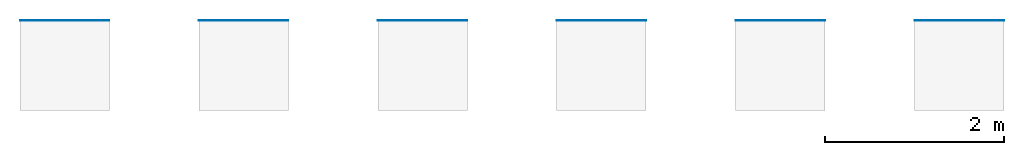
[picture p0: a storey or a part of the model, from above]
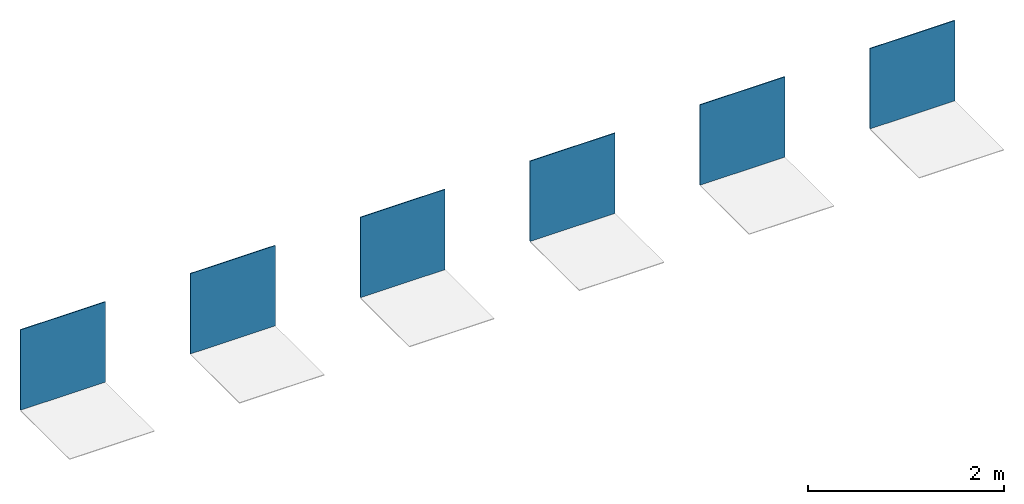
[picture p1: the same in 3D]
Properties of the parts of a building model (IFC2X3)

# File
Description: ViewDefinition [CoordinationView_V2.0]
Time: 2025-06-20T14:48:57
Written by: The EXPRESS Data Manager Version 5.02.0100.07 : 28 Aug 2013
Made in: 21.1.90.15 - Exporter 21.1.90.15 - Alternate UI 21.1.90.15
Comment: STEP Physical File produced by: The EXPRESS Data Manager Version 5.02.0100.07 : 28 Aug 2013 * Module: EDMstepFileFactory/EDMstandAlone * Creation date: Fri Jun 20 14:48:57 2025 * Host: STB002 * Database: C:\Users\LARISS~1\AppData\Local\Temp\234e31d9-e186-458c-9206-d387dea7a233\ee9d88bc-6ba1-4956-a05b-8b28d5bbadac\ifc * Database version: 5507 * Database creation date: Fri Jun 20 14:48:56 2025 * Schema: IFC2X3 * Model: DataRepository.ifc * Model creation date: Fri Jun 20 14:48:57 2025 * Header model: DataRepository.ifc_HeaderModel * Header model creation date: Fri Jun 20 14:48:57 2025 * EDMuser: sdai-user * EDMgroup: sdai-group * License ID and type: 5605 : Permanent license. Expiry date: * EDMstepFileFactory options: 020000

# IfcSite, Default
RefLatitude: 42, 24, 53, 508911; RefLongitude: -71, -15, -29, -58837; RefElevation: 0 mm
Pset_ProductRequirements - Category: Project Information

# IfcBuilding
Pset_BuildingCommon - NumberOfStoreys: 1
Pset_ProductRequirements - Category: Project Information

# IfcBuildingStorey: Level:Level 1, Level 1
LongName: Level 1; Elevation: 0 mm
Pset_AirSideSystemInformation - Name: Level 1
Pset_ProductRequirements - Name: Level 1; Category: Levels

# IfcCovering: Floor:REVIGRÉS-OMNISTONE-MOLTI-30X30-MATTRECT-BONE, Floor:REVIGRÉS-OMNISTONE-MOLTI-30X30-MATTRECT-BONE:155589
In: Level 1
Type - PredefinedType: CLADDING; Material: REVIGRÉS-OMNISTONE-MOLTI-30X30-MATTRECT-BONE 9.8 mm
Type - Pset_CoveringCommon - Reference: 312B127X61; Material: Grés porcelânico
Type - Pset_ElementShading - Roughness: 304.8 mm
Type - Pset_ManufacturerTypeInformation - Manufacturer: REVIGRÉS
Type - Pset_ProductRequirements - Category: Floors
Type - Pset_QuantityTakeOff - Reference: 312B127X61
Type - IFC.REVIGRÉS-Dados do fabricante-Floor Covering - FabricanteURL: https://www.revigres.pt/; ReferenciaModelo: Omnistone; NumeroGlobalDeItemComercial: 312B127X61; Acabamento: MATT RECT; Material: Grés porcelânico; IdentificadorDoOperadorEconomico: 501840856; UrlFabricanteArtigo: https://www.revigres.pt/colecoes/omnistone; PaisOrigem: Portugal
Type - IFC.REVIGRÉS-Dados de desempenho-Floor Covering - Rectilinearidade: ± 0.2% máx.± 0.8 mm; Ortogonalidade: ± 0.2% máx.± 1.5 mm; PlanaridadeDaSuperficie: ± 0.3% máx. ± 1.8 mm; QualidadeDaSuperficie: Cumpre; AbsorcaoDeAgua: < 0.05%; ModuloDeRuptura: > 45 N/mm²; ResistenciaAFlexao: ≥ 3500 N; ResistenciaAAbrasaoProfunda: < 120 mm³; DilatacaoTermicaLinear: ≤ 8,0x10-6 °C-1; ResistenciaAoChoqueTermico: Resiste; DurabilidadeResistenciaAoGeloDegelo: Resiste; ResistenciaAoEscorregamentoDIN51130: R10; ResistenciaAoEscorregamentoDIN51097: B; ResistenciaAoEscorregamentoENV51097: B; ResistenciaAoEscorregamentoENV12633: Class 2; ResistenciaAoEscorregamentoBS7976: >36; ResistenciaAoEscorregamentoANSIA1371: ≥0,42; ResistenciaAoDeslizamentoENV12633: Class 2; ResistenciaAoDeslizamentoBS7976: >36; ResistenciaAsManchas: Class 5; ResistenciaABaixasConcentracoesDeAcidosEAlcalis: Classe LA; ResistenciaAAltasConcentracoesDeAcidosEAlcalis: Classe HA; LibertacaoDeCadmio: 0; LibertacaoDeChumbo: 0
Type - IFC.REVIGRÉS-Dados de especificação-Floor Covering - VariacaoTonalidade: 3; NivelDeTrafego: 5; EPavimento: Sim; ERevestimento: Sim; EExterno: Sim
Type - IFC.REVIGRÉS-Dados geométricos-Floor Covering - AlturaNominal: 9.8 mm; ComprimentoNominal: 29.5 mm; LarguraNominal: 29.5 mm
Type - IFC.REVIGRÉS-Dados de sustentabilidade-Floor Covering - ItemEParcialmenteReciclado: 0; EnergiaTermicaExportada: 0; ItemENovo: Sim; ItemEReciclado: Não; VidaÚtilEsperada: 50; SubstanciasPerigosas: Não; PotencialDeEsgotamentoAbioticoDosRecursosFosseis: 203; PotencialDeEsgotamentoAbioticoDosRecursosNaoFosseisMineraisEMetais: 0.000701; PotencialDeAquecimentoGlobalBiogenico: -0.48; CombustiveisFosseisComPotencialDeAquecimentoGlobal: 13.9; PotencialDeAquecimentoGlobalUsoDoSoloEMudancaDeUsoDoSolo: 0.0246; PotencialDeEutrofizacaoFraccaoDeNutrientesQueAtingemOCompartimentoFinalDeAguaDoce: 0.000189; PotencialDeEutrofizacaoFraccaoDeNutrientesQueAtingemOCompartimentoFinalMarinho: 0.0122; EnergiaRecuperada: 0.00739; ConsumoDeAguaDoce: 0.113; UtilizacaoLiquidaDeAguaDoce: 0.113; ResiduosPerigososEliminados: 0.00221; ResiduosNaoPerigososEliminados: 1.83; MassaTotalDeResiduosRadioactivosEliminados: 0.000394; EnergiaElectricaExportada: 1.55; MateriaisParaRecuperacaoDeEnergia: 0.00739; MateriaisParaReciclagem: 0.0253; UnidadeEPD: 1 m²
Type - IFC.REVIGRÉS-Dados gerais-Floor Covering - Nome: REVIGRÉS-OMNISTONE-MOLTI-30x30-MATT RECT-BONE; TipoProduto: Prensado a seco: grupo BIa UGL | Grés porcelânico técnico; NumeroDeRegistoDAP: EPD-REV-20240006-CCC1-EN; ReferenciaDAP: -; UrlDOP: -
Classification: C3020 (Uniformat)
Pset_CoveringCommon - TotalThickness: 9.8 mm
IFC.REVIGRÉS-Dados do fabricante-Floor Covering - Type: Floor: REVIGRÉS-OMNISTONE-MOLTI-30X30-MATTRECT-BONE
IFC.REVIGRÉS-Dados de desempenho-Floor Covering - Type: Floor: REVIGRÉS-OMNISTONE-MOLTI-30X30-MATTRECT-BONE
IFC.REVIGRÉS-Dados de especificação-Floor Covering - Type: Floor: REVIGRÉS-OMNISTONE-MOLTI-30X30-MATTRECT-BONE
IFC.REVIGRÉS-Dados geométricos-Floor Covering - Type: Floor: REVIGRÉS-OMNISTONE-MOLTI-30X30-MATTRECT-BONE
IFC.REVIGRÉS-Dados de sustentabilidade-Floor Covering - Type: Floor: REVIGRÉS-OMNISTONE-MOLTI-30X30-MATTRECT-BONE

# IfcCovering: Floor:REVIGRÉS-OMNISTONE-MOLTI-30X30-MATTRECT-ICE, Floor:REVIGRÉS-OMNISTONE-MOLTI-30X30-MATTRECT-ICE:156220
In: Level 1
Type - PredefinedType: CLADDING; Material: REVIGRÉS-OMNISTONE-MOLTI-30X30-MATTRECT-ICE 9.8 mm
Type - Pset_CoveringCommon - Reference: 312B127X71; Material: Grés porcelânico
Type - Pset_ElementShading - Roughness: 304.8 mm
Type - Pset_ManufacturerTypeInformation - Manufacturer: REVIGRÉS
Type - Pset_ProductRequirements - Category: Floors
Type - Pset_QuantityTakeOff - Reference: 312B127X71
Type - IFC.REVIGRÉS-Dados do fabricante-Floor Covering - FabricanteURL: https://www.revigres.pt/; ReferenciaModelo: Omnistone; NumeroGlobalDeItemComercial: 312B127X71; Acabamento: MATT RECT; Material: Grés porcelânico; IdentificadorDoOperadorEconomico: 501840856; UrlFabricanteArtigo: https://www.revigres.pt/colecoes/omnistone; PaisOrigem: Portugal
Type - IFC.REVIGRÉS-Dados de desempenho-Floor Covering - Rectilinearidade: ± 0.2% máx.± 0.8 mm; Ortogonalidade: ± 0.2% máx.± 1.5 mm; PlanaridadeDaSuperficie: ± 0.3% máx. ± 1.8 mm; QualidadeDaSuperficie: Cumpre; AbsorcaoDeAgua: < 0.05%; ModuloDeRuptura: > 45 N/mm²; ResistenciaAFlexao: ≥ 3500 N; ResistenciaAAbrasaoProfunda: < 120 mm³; DilatacaoTermicaLinear: ≤ 8,0x10-6 °C-1; ResistenciaAoChoqueTermico: Resiste; DurabilidadeResistenciaAoGeloDegelo: Resiste; ResistenciaAoEscorregamentoDIN51130: R10; ResistenciaAoEscorregamentoDIN51097: B; ResistenciaAoEscorregamentoENV51097: B; ResistenciaAoEscorregamentoENV12633: Class 2; ResistenciaAoEscorregamentoBS7976: >36; ResistenciaAoEscorregamentoANSIA1371: ≥0,42; ResistenciaAoDeslizamentoENV12633: Class 2; ResistenciaAoDeslizamentoBS7976: >36; ResistenciaAsManchas: Class 5; ResistenciaABaixasConcentracoesDeAcidosEAlcalis: Classe LA; ResistenciaAAltasConcentracoesDeAcidosEAlcalis: Classe HA; LibertacaoDeCadmio: 0; LibertacaoDeChumbo: 0
Type - IFC.REVIGRÉS-Dados de especificação-Floor Covering - VariacaoTonalidade: 3; NivelDeTrafego: 5; EPavimento: Sim; ERevestimento: Sim; EExterno: Sim
Type - IFC.REVIGRÉS-Dados geométricos-Floor Covering - AlturaNominal: 9.8 mm; ComprimentoNominal: 29.5 mm; LarguraNominal: 29.5 mm
Type - IFC.REVIGRÉS-Dados de sustentabilidade-Floor Covering - ItemEParcialmenteReciclado: 0; EnergiaTermicaExportada: 0; ItemENovo: Sim; ItemEReciclado: Não; VidaÚtilEsperada: 50; SubstanciasPerigosas: Não; PotencialDeEsgotamentoAbioticoDosRecursosFosseis: 203; PotencialDeEsgotamentoAbioticoDosRecursosNaoFosseisMineraisEMetais: 0.000701; PotencialDeAquecimentoGlobalBiogenico: -0.48; CombustiveisFosseisComPotencialDeAquecimentoGlobal: 13.9; PotencialDeAquecimentoGlobalUsoDoSoloEMudancaDeUsoDoSolo: 0.0246; PotencialDeEutrofizacaoFraccaoDeNutrientesQueAtingemOCompartimentoFinalDeAguaDoce: 0.000189; PotencialDeEutrofizacaoFraccaoDeNutrientesQueAtingemOCompartimentoFinalMarinho: 0.0122; EnergiaRecuperada: 0.00739; ConsumoDeAguaDoce: 0.113; UtilizacaoLiquidaDeAguaDoce: 0.113; ResiduosPerigososEliminados: 0.00221; ResiduosNaoPerigososEliminados: 1.83; MassaTotalDeResiduosRadioactivosEliminados: 0.000394; EnergiaElectricaExportada: 1.55; MateriaisParaRecuperacaoDeEnergia: 0.00739; MateriaisParaReciclagem: 0.0253; UnidadeEPD: 1 m²
Type - IFC.REVIGRÉS-Dados gerais-Floor Covering - Nome: REVIGRÉS-OMNISTONE-MOLTI-30x30-MATT RECT-ICE; TipoProduto: Prensado a seco: grupo BIa UGL | Grés porcelânico técnico; NumeroDeRegistoDAP: EPD-REV-20240006-CCC1-EN; ReferenciaDAP: -; UrlDOP: -
Classification: C3020 (Uniformat)
Pset_CoveringCommon - TotalThickness: 9.8 mm
IFC.REVIGRÉS-Dados do fabricante-Floor Covering - Type: Floor: REVIGRÉS-OMNISTONE-MOLTI-30X30-MATTRECT-ICE
IFC.REVIGRÉS-Dados de desempenho-Floor Covering - Type: Floor: REVIGRÉS-OMNISTONE-MOLTI-30X30-MATTRECT-ICE
IFC.REVIGRÉS-Dados de especificação-Floor Covering - Type: Floor: REVIGRÉS-OMNISTONE-MOLTI-30X30-MATTRECT-ICE
IFC.REVIGRÉS-Dados geométricos-Floor Covering - Type: Floor: REVIGRÉS-OMNISTONE-MOLTI-30X30-MATTRECT-ICE
IFC.REVIGRÉS-Dados de sustentabilidade-Floor Covering - Type: Floor: REVIGRÉS-OMNISTONE-MOLTI-30X30-MATTRECT-ICE

# IfcCovering: Floor:REVIGRÉS-OMNISTONE-MOLTI-30X30-MATTRECT-IRON, Floor:REVIGRÉS-OMNISTONE-MOLTI-30X30-MATTRECT-IRON:156297
In: Level 1
Type - PredefinedType: CLADDING; Material: REVIGRÉS-OMNISTONE-MOLTI-30X30-MATTRECT-IRON 9.8 mm
Type - Pset_CoveringCommon - Reference: 312B127X81; Material: Grés porcelânico
Type - Pset_ElementShading - Roughness: 304.8 mm
Type - Pset_ManufacturerTypeInformation - Manufacturer: REVIGRÉS
Type - Pset_ProductRequirements - Category: Floors
Type - Pset_QuantityTakeOff - Reference: 312B127X81
Type - IFC.REVIGRÉS-Dados do fabricante-Floor Covering - FabricanteURL: https://www.revigres.pt/; ReferenciaModelo: Omnistone; NumeroGlobalDeItemComercial: 312B127X81; Acabamento: MATT RECT; Material: Grés porcelânico; IdentificadorDoOperadorEconomico: 501840856; UrlFabricanteArtigo: https://www.revigres.pt/colecoes/omnistone; PaisOrigem: Portugal
Type - IFC.REVIGRÉS-Dados de desempenho-Floor Covering - Rectilinearidade: ± 0.2% máx.± 0.8 mm; Ortogonalidade: ± 0.2% máx.± 1.5 mm; PlanaridadeDaSuperficie: ± 0.3% máx. ± 1.8 mm; QualidadeDaSuperficie: Cumpre; AbsorcaoDeAgua: < 0.05%; ModuloDeRuptura: > 45 N/mm²; ResistenciaAFlexao: ≥ 3500 N; ResistenciaAAbrasaoProfunda: < 120 mm³; DilatacaoTermicaLinear: ≤ 8,0x10-6 °C-1; ResistenciaAoChoqueTermico: Resiste; DurabilidadeResistenciaAoGeloDegelo: Resiste; ResistenciaAoEscorregamentoDIN51130: R10; ResistenciaAoEscorregamentoDIN51097: B; ResistenciaAoEscorregamentoENV51097: B; ResistenciaAoEscorregamentoENV12633: Class 2; ResistenciaAoEscorregamentoBS7976: >36; ResistenciaAoEscorregamentoANSIA1371: ≥0,42; ResistenciaAoDeslizamentoENV12633: Class 2; ResistenciaAoDeslizamentoBS7976: >36; ResistenciaAsManchas: Class 5; ResistenciaABaixasConcentracoesDeAcidosEAlcalis: Classe LA; ResistenciaAAltasConcentracoesDeAcidosEAlcalis: Classe HA; LibertacaoDeCadmio: 0; LibertacaoDeChumbo: 0
Type - IFC.REVIGRÉS-Dados de especificação-Floor Covering - VariacaoTonalidade: 3; NivelDeTrafego: 5; EPavimento: Sim; ERevestimento: Sim; EExterno: Sim
Type - IFC.REVIGRÉS-Dados geométricos-Floor Covering - AlturaNominal: 9.8 mm; ComprimentoNominal: 29.5 mm; LarguraNominal: 29.5 mm
Type - IFC.REVIGRÉS-Dados de sustentabilidade-Floor Covering - EnergiaTermicaExportada: 0; ItemENovo: Sim; ItemEParcialmenteReciclado: 0.14; ItemEReciclado: Sim; VidaÚtilEsperada: 50; SubstanciasPerigosas: Não; PotencialDeEsgotamentoAbioticoDosRecursosFosseis: 203; PotencialDeEsgotamentoAbioticoDosRecursosNaoFosseisMineraisEMetais: 0.000701; PotencialDeAquecimentoGlobalBiogenico: -0.48; CombustiveisFosseisComPotencialDeAquecimentoGlobal: 13.9; PotencialDeAquecimentoGlobalUsoDoSoloEMudancaDeUsoDoSolo: 0.0246; PotencialDeEutrofizacaoFraccaoDeNutrientesQueAtingemOCompartimentoFinalDeAguaDoce: 0.000189; PotencialDeEutrofizacaoFraccaoDeNutrientesQueAtingemOCompartimentoFinalMarinho: 0.0122; EnergiaRecuperada: 0.00739; ConsumoDeAguaDoce: 0.113; UtilizacaoLiquidaDeAguaDoce: 0.113; ResiduosPerigososEliminados: 0.00221; ResiduosNaoPerigososEliminados: 1.83; MassaTotalDeResiduosRadioactivosEliminados: 0.000394; EnergiaElectricaExportada: 1.55; MateriaisParaRecuperacaoDeEnergia: 0.00739; MateriaisParaReciclagem: 0.0253; UnidadeEPD: 1 m²
Type - IFC.REVIGRÉS-Dados gerais-Floor Covering - Nome: REVIGRÉS-OMNISTONE-MOLTI-30x30-MATT RECT-IRON; TipoProduto: Prensado a seco: grupo BIa UGL | Grés porcelânico técnico; NumeroDeRegistoDAP: EPD-REV-20240006-CCC1-EN; ReferenciaDAP: -; UrlDOP: -
Classification: C3020 (Uniformat)
Pset_CoveringCommon - TotalThickness: 9.8 mm
IFC.REVIGRÉS-Dados do fabricante-Floor Covering - Type: Floor: REVIGRÉS-OMNISTONE-MOLTI-30X30-MATTRECT-IRON
IFC.REVIGRÉS-Dados de desempenho-Floor Covering - Type: Floor: REVIGRÉS-OMNISTONE-MOLTI-30X30-MATTRECT-IRON
IFC.REVIGRÉS-Dados de especificação-Floor Covering - Type: Floor: REVIGRÉS-OMNISTONE-MOLTI-30X30-MATTRECT-IRON
IFC.REVIGRÉS-Dados geométricos-Floor Covering - Type: Floor: REVIGRÉS-OMNISTONE-MOLTI-30X30-MATTRECT-IRON
IFC.REVIGRÉS-Dados de sustentabilidade-Floor Covering - Type: Floor: REVIGRÉS-OMNISTONE-MOLTI-30X30-MATTRECT-IRON

# IfcCovering: Floor:REVIGRÉS-OMNISTONE-MOLTI-30X30-MATTRECT-JET, Floor:REVIGRÉS-OMNISTONE-MOLTI-30X30-MATTRECT-JET:156364
In: Level 1
Type - PredefinedType: CLADDING; Material: REVIGRÉS-OMNISTONE-MOLTI-30X30-MATTRECT-JET 9.8 mm
Type - Pset_CoveringCommon - Reference: 312B127X91; Material: Grés porcelânico
Type - Pset_ElementShading - Roughness: 304.8 mm
Type - Pset_ManufacturerTypeInformation - Manufacturer: REVIGRÉS
Type - Pset_ProductRequirements - Category: Floors
Type - Pset_QuantityTakeOff - Reference: 312B127X91
Type - IFC.REVIGRÉS-Dados do fabricante-Floor Covering - FabricanteURL: https://www.revigres.pt/; ReferenciaModelo: Omnistone; NumeroGlobalDeItemComercial: 312B127X91; Acabamento: MATT RECT; Material: Grés porcelânico; IdentificadorDoOperadorEconomico: 501840856; UrlFabricanteArtigo: https://www.revigres.pt/colecoes/omnistone; PaisOrigem: Portugal
Type - IFC.REVIGRÉS-Dados de desempenho-Floor Covering - Rectilinearidade: ± 0.2% máx.± 0.8 mm; Ortogonalidade: ± 0.2% máx.± 1.5 mm; PlanaridadeDaSuperficie: ± 0.3% máx. ± 1.8 mm; QualidadeDaSuperficie: Cumpre; AbsorcaoDeAgua: < 0.05%; ModuloDeRuptura: > 45 N/mm²; ResistenciaAFlexao: ≥ 3500 N; ResistenciaAAbrasaoProfunda: < 120 mm³; DilatacaoTermicaLinear: ≤ 8,0x10-6 °C-1; ResistenciaAoChoqueTermico: Resiste; DurabilidadeResistenciaAoGeloDegelo: Resiste; ResistenciaAoEscorregamentoDIN51130: R10; ResistenciaAoEscorregamentoDIN51097: B; ResistenciaAoEscorregamentoENV51097: B; ResistenciaAoEscorregamentoENV12633: Class 2; ResistenciaAoEscorregamentoBS7976: >36; ResistenciaAoEscorregamentoANSIA1371: ≥0,42; ResistenciaAoDeslizamentoENV12633: Class 2; ResistenciaAoDeslizamentoBS7976: >36; ResistenciaAsManchas: Class 5; ResistenciaABaixasConcentracoesDeAcidosEAlcalis: Classe LA; ResistenciaAAltasConcentracoesDeAcidosEAlcalis: Classe HA; LibertacaoDeCadmio: 0; LibertacaoDeChumbo: 0
Type - IFC.REVIGRÉS-Dados de especificação-Floor Covering - VariacaoTonalidade: 3; NivelDeTrafego: 5; EPavimento: Sim; ERevestimento: Sim; EExterno: Sim
Type - IFC.REVIGRÉS-Dados geométricos-Floor Covering - AlturaNominal: 9.8 mm; ComprimentoNominal: 29.5 mm; LarguraNominal: 29.5 mm
Type - IFC.REVIGRÉS-Dados de sustentabilidade-Floor Covering - ItemEParcialmenteReciclado: 0; EnergiaTermicaExportada: 0; ItemENovo: Sim; ItemEReciclado: Não; VidaÚtilEsperada: 50; SubstanciasPerigosas: Não; PotencialDeEsgotamentoAbioticoDosRecursosFosseis: 203; PotencialDeEsgotamentoAbioticoDosRecursosNaoFosseisMineraisEMetais: 0.000701; PotencialDeAquecimentoGlobalBiogenico: -0.48; CombustiveisFosseisComPotencialDeAquecimentoGlobal: 13.9; PotencialDeAquecimentoGlobalUsoDoSoloEMudancaDeUsoDoSolo: 0.0246; PotencialDeEutrofizacaoFraccaoDeNutrientesQueAtingemOCompartimentoFinalDeAguaDoce: 0.000189; PotencialDeEutrofizacaoFraccaoDeNutrientesQueAtingemOCompartimentoFinalMarinho: 0.0122; EnergiaRecuperada: 0.00739; ConsumoDeAguaDoce: 0.113; UtilizacaoLiquidaDeAguaDoce: 0.113; ResiduosPerigososEliminados: 0.00221; ResiduosNaoPerigososEliminados: 1.83; MassaTotalDeResiduosRadioactivosEliminados: 0.000394; EnergiaElectricaExportada: 1.55; MateriaisParaRecuperacaoDeEnergia: 0.00739; MateriaisParaReciclagem: 0.0253; UnidadeEPD: 1 m²
Type - IFC.REVIGRÉS-Dados gerais-Floor Covering - Nome: REVIGRÉS-OMNISTONE-MOLTI-30x30-MATT RECT-JET; TipoProduto: Prensado a seco: grupo BIa UGL | Grés porcelânico técnico; NumeroDeRegistoDAP: EPD-REV-20240006-CCC1-EN; ReferenciaDAP: -; UrlDOP: -
Classification: C3020 (Uniformat)
Pset_CoveringCommon - TotalThickness: 9.8 mm
IFC.REVIGRÉS-Dados do fabricante-Floor Covering - Type: Floor: REVIGRÉS-OMNISTONE-MOLTI-30X30-MATTRECT-JET
IFC.REVIGRÉS-Dados de desempenho-Floor Covering - Type: Floor: REVIGRÉS-OMNISTONE-MOLTI-30X30-MATTRECT-JET
IFC.REVIGRÉS-Dados de especificação-Floor Covering - Type: Floor: REVIGRÉS-OMNISTONE-MOLTI-30X30-MATTRECT-JET
IFC.REVIGRÉS-Dados geométricos-Floor Covering - Type: Floor: REVIGRÉS-OMNISTONE-MOLTI-30X30-MATTRECT-JET
IFC.REVIGRÉS-Dados de sustentabilidade-Floor Covering - Type: Floor: REVIGRÉS-OMNISTONE-MOLTI-30X30-MATTRECT-JET

# IfcCovering: Floor:REVIGRÉS-OMNISTONE-MOLTI-30X30-MATTRECT-PLATINA, Floor:REVIGRÉS-OMNISTONE-MOLTI-30X30-MATTRECT-PLATINA:156444
In: Level 1
Type - PredefinedType: CLADDING; Material: REVIGRÉS-OMNISTONE-MOLTI-30X30-MATTRECT-PLATINA 9.8 mm
Type - Pset_CoveringCommon - Reference: 312B128X01; Material: Grés porcelânico
Type - Pset_ElementShading - Roughness: 304.8 mm
Type - Pset_ManufacturerTypeInformation - Manufacturer: REVIGRÉS
Type - Pset_ProductRequirements - Category: Floors
Type - Pset_QuantityTakeOff - Reference: 312B128X01
Type - IFC.REVIGRÉS-Dados do fabricante-Floor Covering - FabricanteURL: https://www.revigres.pt/; ReferenciaModelo: Omnistone; NumeroGlobalDeItemComercial: 312B128X01; Acabamento: MATT RECT; Material: Grés porcelânico; IdentificadorDoOperadorEconomico: 501840856; UrlFabricanteArtigo: https://www.revigres.pt/colecoes/omnistone; PaisOrigem: Portugal
Type - IFC.REVIGRÉS-Dados de desempenho-Floor Covering - Rectilinearidade: ± 0.2% máx.± 0.8 mm; Ortogonalidade: ± 0.2% máx.± 1.5 mm; PlanaridadeDaSuperficie: ± 0.3% máx. ± 1.8 mm; QualidadeDaSuperficie: Cumpre; AbsorcaoDeAgua: < 0.05%; ModuloDeRuptura: > 45 N/mm²; ResistenciaAFlexao: ≥ 3500 N; ResistenciaAAbrasaoProfunda: < 120 mm³; DilatacaoTermicaLinear: ≤ 8,0x10-6 °C-1; ResistenciaAoChoqueTermico: Resiste; DurabilidadeResistenciaAoGeloDegelo: Resiste; ResistenciaAoEscorregamentoDIN51130: R10; ResistenciaAoEscorregamentoDIN51097: B; ResistenciaAoEscorregamentoENV51097: B; ResistenciaAoEscorregamentoENV12633: Class 2; ResistenciaAoEscorregamentoBS7976: >36; ResistenciaAoEscorregamentoANSIA1371: ≥0,42; ResistenciaAoDeslizamentoENV12633: Class 2; ResistenciaAoDeslizamentoBS7976: >36; ResistenciaAsManchas: Class 5; ResistenciaABaixasConcentracoesDeAcidosEAlcalis: Classe LA; ResistenciaAAltasConcentracoesDeAcidosEAlcalis: Classe HA; LibertacaoDeCadmio: 0; LibertacaoDeChumbo: 0
Type - IFC.REVIGRÉS-Dados de especificação-Floor Covering - VariacaoTonalidade: 3; NivelDeTrafego: 5; EPavimento: Sim; ERevestimento: Sim; EExterno: Sim
Type - IFC.REVIGRÉS-Dados geométricos-Floor Covering - AlturaNominal: 9.8 mm; ComprimentoNominal: 29.5 mm; LarguraNominal: 29.5 mm
Type - IFC.REVIGRÉS-Dados de sustentabilidade-Floor Covering - ItemEParcialmenteReciclado: 0; EnergiaTermicaExportada: 0; ItemENovo: Sim; ItemEReciclado: Não; VidaÚtilEsperada: 50; SubstanciasPerigosas: Não; PotencialDeEsgotamentoAbioticoDosRecursosFosseis: 203; PotencialDeEsgotamentoAbioticoDosRecursosNaoFosseisMineraisEMetais: 0.000701; PotencialDeAquecimentoGlobalBiogenico: -0.48; CombustiveisFosseisComPotencialDeAquecimentoGlobal: 13.9; PotencialDeAquecimentoGlobalUsoDoSoloEMudancaDeUsoDoSolo: 0.0246; PotencialDeEutrofizacaoFraccaoDeNutrientesQueAtingemOCompartimentoFinalDeAguaDoce: 0.000189; PotencialDeEutrofizacaoFraccaoDeNutrientesQueAtingemOCompartimentoFinalMarinho: 0.0122; EnergiaRecuperada: 0.00739; ConsumoDeAguaDoce: 0.113; UtilizacaoLiquidaDeAguaDoce: 0.113; ResiduosPerigososEliminados: 0.00221; ResiduosNaoPerigososEliminados: 1.83; MassaTotalDeResiduosRadioactivosEliminados: 0.000394; EnergiaElectricaExportada: 1.55; MateriaisParaRecuperacaoDeEnergia: 0.00739; MateriaisParaReciclagem: 0.0253; UnidadeEPD: 1 m²
Type - IFC.REVIGRÉS-Dados gerais-Floor Covering - Nome: REVIGRÉS-OMNISTONE-MOLTI-30x30-MATT RECT-PLATINA; TipoProduto: Prensado a seco: grupo BIa UGL | Grés porcelânico técnico; NumeroDeRegistoDAP: EPD-REV-20240006-CCC1-EN; ReferenciaDAP: -; UrlDOP: -
Classification: C3020 (Uniformat)
Pset_CoveringCommon - TotalThickness: 9.8 mm
IFC.REVIGRÉS-Dados do fabricante-Floor Covering - Type: Floor: REVIGRÉS-OMNISTONE-MOLTI-30X30-MATTRECT-PLATINA
IFC.REVIGRÉS-Dados de desempenho-Floor Covering - Type: Floor: REVIGRÉS-OMNISTONE-MOLTI-30X30-MATTRECT-PLATINA
IFC.REVIGRÉS-Dados de especificação-Floor Covering - Type: Floor: REVIGRÉS-OMNISTONE-MOLTI-30X30-MATTRECT-PLATINA
IFC.REVIGRÉS-Dados geométricos-Floor Covering - Type: Floor: REVIGRÉS-OMNISTONE-MOLTI-30X30-MATTRECT-PLATINA
IFC.REVIGRÉS-Dados de sustentabilidade-Floor Covering - Type: Floor: REVIGRÉS-OMNISTONE-MOLTI-30X30-MATTRECT-PLATINA

# IfcCovering: Floor:REVIGRÉS-OMNISTONE-MOLTI-30X30-MATTRECT-ROPE, Floor:REVIGRÉS-OMNISTONE-MOLTI-30X30-MATTRECT-ROPE:156527
In: Level 1
Type - PredefinedType: CLADDING; Material: REVIGRÉS-OMNISTONE-MOLTI-30X30-MATTRECT-ROPE 9.8 mm
Type - Pset_CoveringCommon - Reference: 312B128X11; Material: Grés porcelânico
Type - Pset_ElementShading - Roughness: 304.8 mm
Type - Pset_ManufacturerTypeInformation - Manufacturer: REVIGRÉS
Type - Pset_ProductRequirements - Category: Floors
Type - Pset_QuantityTakeOff - Reference: 312B128X11
Type - IFC.REVIGRÉS-Dados do fabricante-Floor Covering - FabricanteURL: https://www.revigres.pt/; ReferenciaModelo: Omnistone; NumeroGlobalDeItemComercial: 312B128X11; Acabamento: MATT RECT; Material: Grés porcelânico; IdentificadorDoOperadorEconomico: 501840856; UrlFabricanteArtigo: https://www.revigres.pt/colecoes/omnistone; PaisOrigem: Portugal
Type - IFC.REVIGRÉS-Dados de desempenho-Floor Covering - Rectilinearidade: ± 0.2% máx.± 0.8 mm; Ortogonalidade: ± 0.2% máx.± 1.5 mm; PlanaridadeDaSuperficie: ± 0.3% máx. ± 1.8 mm; QualidadeDaSuperficie: Cumpre; AbsorcaoDeAgua: < 0.05%; ModuloDeRuptura: > 45 N/mm²; ResistenciaAFlexao: ≥ 3500 N; ResistenciaAAbrasaoProfunda: < 120 mm³; DilatacaoTermicaLinear: ≤ 8,0x10-6 °C-1; ResistenciaAoChoqueTermico: Resiste; DurabilidadeResistenciaAoGeloDegelo: Resiste; ResistenciaAoEscorregamentoDIN51130: R10; ResistenciaAoEscorregamentoDIN51097: B; ResistenciaAoEscorregamentoENV51097: B; ResistenciaAoEscorregamentoENV12633: Class 2; ResistenciaAoEscorregamentoBS7976: >36; ResistenciaAoEscorregamentoANSIA1371: ≥0,42; ResistenciaAoDeslizamentoENV12633: Class 2; ResistenciaAoDeslizamentoBS7976: >36; ResistenciaAsManchas: Class 5; ResistenciaABaixasConcentracoesDeAcidosEAlcalis: Classe LA; ResistenciaAAltasConcentracoesDeAcidosEAlcalis: Classe HA; LibertacaoDeCadmio: 0; LibertacaoDeChumbo: 0
Type - IFC.REVIGRÉS-Dados de especificação-Floor Covering - VariacaoTonalidade: 3; NivelDeTrafego: 5; EPavimento: Sim; ERevestimento: Sim; EExterno: Sim
Type - IFC.REVIGRÉS-Dados geométricos-Floor Covering - AlturaNominal: 9.8 mm; ComprimentoNominal: 29.5 mm; LarguraNominal: 29.5 mm
Type - IFC.REVIGRÉS-Dados de sustentabilidade-Floor Covering - ItemEParcialmenteReciclado: 0; EnergiaTermicaExportada: 0; ItemENovo: Sim; ItemEReciclado: Não; VidaÚtilEsperada: 50; SubstanciasPerigosas: Não; PotencialDeEsgotamentoAbioticoDosRecursosFosseis: 203; PotencialDeEsgotamentoAbioticoDosRecursosNaoFosseisMineraisEMetais: 0.000701; PotencialDeAquecimentoGlobalBiogenico: -0.48; CombustiveisFosseisComPotencialDeAquecimentoGlobal: 13.9; PotencialDeAquecimentoGlobalUsoDoSoloEMudancaDeUsoDoSolo: 0.0246; PotencialDeEutrofizacaoFraccaoDeNutrientesQueAtingemOCompartimentoFinalDeAguaDoce: 0.000189; PotencialDeEutrofizacaoFraccaoDeNutrientesQueAtingemOCompartimentoFinalMarinho: 0.0122; EnergiaRecuperada: 0.00739; ConsumoDeAguaDoce: 0.113; UtilizacaoLiquidaDeAguaDoce: 0.113; ResiduosPerigososEliminados: 0.00221; ResiduosNaoPerigososEliminados: 1.83; MassaTotalDeResiduosRadioactivosEliminados: 0.000394; EnergiaElectricaExportada: 1.55; MateriaisParaRecuperacaoDeEnergia: 0.00739; MateriaisParaReciclagem: 0.0253; UnidadeEPD: 1 m²
Type - IFC.REVIGRÉS-Dados gerais-Floor Covering - Nome: REVIGRÉS-OMNISTONE-MOLTI-30x30-MATT RECT-ROPE; TipoProduto: Prensado a seco: grupo BIa UGL | Grés porcelânico técnico; NumeroDeRegistoDAP: EPD-REV-20240006-CCC1-EN; ReferenciaDAP: -; UrlDOP: -
Classification: C3020 (Uniformat)
Pset_CoveringCommon - TotalThickness: 9.8 mm
IFC.REVIGRÉS-Dados do fabricante-Floor Covering - Type: Floor: REVIGRÉS-OMNISTONE-MOLTI-30X30-MATTRECT-ROPE
IFC.REVIGRÉS-Dados de desempenho-Floor Covering - Type: Floor: REVIGRÉS-OMNISTONE-MOLTI-30X30-MATTRECT-ROPE
IFC.REVIGRÉS-Dados de especificação-Floor Covering - Type: Floor: REVIGRÉS-OMNISTONE-MOLTI-30X30-MATTRECT-ROPE
IFC.REVIGRÉS-Dados geométricos-Floor Covering - Type: Floor: REVIGRÉS-OMNISTONE-MOLTI-30X30-MATTRECT-ROPE
IFC.REVIGRÉS-Dados de sustentabilidade-Floor Covering - Type: Floor: REVIGRÉS-OMNISTONE-MOLTI-30X30-MATTRECT-ROPE

# IfcWallStandardCase: Basic Wall:REVIGRÉS-OMNISTONE-MOLTI-30X30-MATTRECT-BONE, Basic Wall:REVIGRÉS-OMNISTONE-MOLTI-30X30-MATTRECT-BONE:155597
In: Level 1
Type - PredefinedType: STANDARD; Material: REVIGRÉS-OMNISTONE-MOLTI-30X30-MATTRECT-BONE 9.8 mm
Type - Pset_ElementShading - Roughness: 304.8 mm
Type - Pset_ManufacturerTypeInformation - Manufacturer: REVIGRÉS
Type - Pset_ProductRequirements - Category: Walls
Type - Pset_QuantityTakeOff - Reference: 312B127X61
Type - Pset_ReinforcementBarPitchOfWall - Description: Stone effect in wall and floor porcelain tile.; Reference: 312B127X61
Type - Pset_WallCommon - Reference: 312B127X61; IsExternal: no
Type - IFC.REVIGRÉS-Dados do fabricante-Wall Covering - FabricanteURL: https://www.revigres.pt/; ReferenciaModelo: Omnistone; NumeroGlobalDeItemComercial: 312B127X61; Acabamento: MATT RECT; Material: Grés porcelânico; IdentificadorDoOperadorEconomico: 501840856; UrlFabricanteArtigo: https://www.revigres.pt/colecoes/omnistone; PaisOrigem: Portugal
Type - IFC.REVIGRÉS-Dados de desempenho-Wall Covering - Rectilinearidade: ± 0.2% máx.± 0.8 mm; Ortogonalidade: ± 0.2% máx.± 1.5 mm; PlanaridadeDaSuperficie: ± 0.3% máx. ± 1.8 mm; QualidadeDaSuperficie: Cumpre; AbsorcaoDeAgua: < 0.05%; ModuloDeRuptura: > 45 N/mm²; ResistenciaAFlexao: ≥ 3500 N; ResistenciaAAbrasaoProfunda: < 120 mm³; DilatacaoTermicaLinear: ≤ 8,0x10-6 °C-1; ResistenciaAoChoqueTermico: Resiste; DurabilidadeResistenciaAoGeloDegelo: Resiste; ResistenciaAoEscorregamentoDIN51130: R10; ResistenciaAoEscorregamentoDIN51097: B; ResistenciaAoEscorregamentoENV51097: B; ResistenciaAoEscorregamentoENV12633: Class 2; ResistenciaAoEscorregamentoBS7976: >36; ResistenciaAoEscorregamentoANSIA1371: ≥0,42; ResistenciaAoDeslizamentoENV12633: Class 2; ResistenciaAoDeslizamentoBS7976: >36; ResistenciaAsManchas: Class 5; ResistenciaABaixasConcentracoesDeAcidosEAlcalis: Classe LA; ResistenciaAAltasConcentracoesDeAcidosEAlcalis: Classe HA; LibertacaoDeCadmio: 0; LibertacaoDeChumbo: 0
Type - IFC.REVIGRÉS-Dados de especificação-Wall Covering - VariacaoTonalidade: 3; NivelDeTrafego: 5; EPavimento: Sim; ERevestimento: Sim; EExterno: Sim
Type - IFC.REVIGRÉS-Dados geométricos-Wall Covering - AlturaNominal: 9.8 mm; ComprimentoNominal: 29.5 mm; LarguraNominal: 29.5 mm
Type - IFC.REVIGRÉS-Dados de sustentabilidade-Wall Covering - ItemEParcialmenteReciclado: 0; EnergiaTermicaExportada: 0; ItemENovo: Sim; ItemEReciclado: Não; VidaÚtilEsperada: 50; SubstanciasPerigosas: Não; PotencialDeEsgotamentoAbioticoDosRecursosFosseis: 203; PotencialDeEsgotamentoAbioticoDosRecursosNaoFosseisMineraisEMetais: 0.000701; PotencialDeAquecimentoGlobalBiogenico: -0.48; CombustiveisFosseisComPotencialDeAquecimentoGlobal: 13.9; PotencialDeAquecimentoGlobalUsoDoSoloEMudancaDeUsoDoSolo: 0.0246; PotencialDeEutrofizacaoFraccaoDeNutrientesQueAtingemOCompartimentoFinalDeAguaDoce: 0.000189; PotencialDeEutrofizacaoFraccaoDeNutrientesQueAtingemOCompartimentoFinalMarinho: 0.0122; PotencialPrivacaoDeAguaConsumoDeAguaPonderado: 4.5; EnergiaRecuperada: 0.00739; ConsumoDeAguaDoce: 0.113; UtilizacaoLiquidaDeAguaDoce: 0.113; ResiduosPerigososEliminados: 0.00221; ResiduosNaoPerigososEliminados: 1.83; MassaTotalDeResiduosRadioactivosEliminados: 0.000394; EnergiaElectricaExportada: 1.55; MateriaisParaRecuperacaoDeEnergia: 0.00739; MateriaisParaReciclagem: 0.0253; UnidadeEPD: 1 m²
Type - IFC.REVIGRÉS-Dados gerais-Wall Covering - Nome: REVIGRÉS-OMNISTONE-MOLTI-30x30-MATT RECT-BONE; TipoProduto: Prensado a seco: grupo BIa UGL | Grés porcelânico técnico; NumeroDeRegistoDAP: EPD-REV-20240006-CCC1-EN; ReferenciaDAP: -; UrlDOP: -
Classification: C3010 (Uniformat)
Pset_WallCommon - ExtendToStructure: no; LoadBearing: no
IFC.REVIGRÉS-Dados do fabricante-Wall Covering - Type: Basic Wall: REVIGRÉS-OMNISTONE-MOLTI-30X30-MATTRECT-BONE
IFC.REVIGRÉS-Dados de desempenho-Wall Covering - Type: Basic Wall: REVIGRÉS-OMNISTONE-MOLTI-30X30-MATTRECT-BONE
IFC.REVIGRÉS-Dados de especificação-Wall Covering - Type: Basic Wall: REVIGRÉS-OMNISTONE-MOLTI-30X30-MATTRECT-BONE
IFC.REVIGRÉS-Dados geométricos-Wall Covering - Type: Basic Wall: REVIGRÉS-OMNISTONE-MOLTI-30X30-MATTRECT-BONE
IFC.REVIGRÉS-Dados de sustentabilidade-Wall Covering - Type: Basic Wall: REVIGRÉS-OMNISTONE-MOLTI-30X30-MATTRECT-BONE

# IfcWallStandardCase: Basic Wall:REVIGRÉS-OMNISTONE-MOLTI-30X30-MATTRECT-ICE, Basic Wall:REVIGRÉS-OMNISTONE-MOLTI-30X30-MATTRECT-ICE:156225
In: Level 1
Type - PredefinedType: STANDARD; Material: REVIGRÉS-OMNISTONE-MOLTI-30X30-MATTRECT-ICE 9.8 mm
Type - Pset_ElementShading - Roughness: 304.8 mm
Type - Pset_ManufacturerTypeInformation - Manufacturer: REVIGRÉS
Type - Pset_ProductRequirements - Category: Walls
Type - Pset_QuantityTakeOff - Reference: 312B127X71
Type - Pset_ReinforcementBarPitchOfWall - Description: Stone effect in wall and floor porcelain tile; Reference: 312B127X71
Type - Pset_WallCommon - IsExternal: no; Reference: 312B127X71
Type - IFC.REVIGRÉS-Dados do fabricante-Wall Covering - FabricanteURL: https://www.revigres.pt/; ReferenciaModelo: Omnistone; NumeroGlobalDeItemComercial: 312B127X71; Acabamento: MATT RECT; Material: Grés porcelânico; IdentificadorDoOperadorEconomico: 501840856; UrlFabricanteArtigo: https://www.revigres.pt/colecoes/omnistone; PaisOrigem: Portugal
Type - IFC.REVIGRÉS-Dados de desempenho-Wall Covering - Rectilinearidade: ± 0.2% máx.± 0.8 mm; Ortogonalidade: ± 0.2% máx.± 1.5 mm; PlanaridadeDaSuperficie: ± 0.3% máx. ± 1.8 mm; QualidadeDaSuperficie: Cumpre; AbsorcaoDeAgua: < 0.05%; ModuloDeRuptura: > 45 N/mm²; ResistenciaAFlexao: ≥ 3500 N; ResistenciaAAbrasaoProfunda: < 120 mm³; DilatacaoTermicaLinear: ≤ 8,0x10-6 °C-1; ResistenciaAoChoqueTermico: Resiste; DurabilidadeResistenciaAoGeloDegelo: Resiste; ResistenciaAoEscorregamentoDIN51130: R10; ResistenciaAoEscorregamentoDIN51097: B; ResistenciaAoEscorregamentoENV51097: B; ResistenciaAoEscorregamentoENV12633: Class 2; ResistenciaAoEscorregamentoBS7976: >36; ResistenciaAoEscorregamentoANSIA1371: ≥0,42; ResistenciaAoDeslizamentoENV12633: Class 2; ResistenciaAoDeslizamentoBS7976: >36; ResistenciaAsManchas: Class 5; ResistenciaABaixasConcentracoesDeAcidosEAlcalis: Classe LA; ResistenciaAAltasConcentracoesDeAcidosEAlcalis: Classe HA; LibertacaoDeCadmio: 0; LibertacaoDeChumbo: 0
Type - IFC.REVIGRÉS-Dados de especificação-Wall Covering - VariacaoTonalidade: 3; NivelDeTrafego: 5; EPavimento: Sim; ERevestimento: Sim; EExterno: Sim
Type - IFC.REVIGRÉS-Dados geométricos-Wall Covering - AlturaNominal: 9.8 mm; ComprimentoNominal: 29.5 mm; LarguraNominal: 29.5 mm
Type - IFC.REVIGRÉS-Dados de sustentabilidade-Wall Covering - ItemEParcialmenteReciclado: 0; EnergiaTermicaExportada: 0; PotencialPrivacaoDeAguaConsumoDeAguaPonderado: 4.5; ItemENovo: Sim; ItemEReciclado: Não; VidaÚtilEsperada: 50; SubstanciasPerigosas: Não; PotencialDeEsgotamentoAbioticoDosRecursosFosseis: 203; PotencialDeEsgotamentoAbioticoDosRecursosNaoFosseisMineraisEMetais: 0.000701; PotencialDeAquecimentoGlobalBiogenico: -0.48; CombustiveisFosseisComPotencialDeAquecimentoGlobal: 13.9; PotencialDeAquecimentoGlobalUsoDoSoloEMudancaDeUsoDoSolo: 0.0246; PotencialDeEutrofizacaoFraccaoDeNutrientesQueAtingemOCompartimentoFinalDeAguaDoce: 0.000189; PotencialDeEutrofizacaoFraccaoDeNutrientesQueAtingemOCompartimentoFinalMarinho: 0.0122; EnergiaRecuperada: 0.00739; ConsumoDeAguaDoce: 0.113; UtilizacaoLiquidaDeAguaDoce: 0.113; ResiduosPerigososEliminados: 0.00221; ResiduosNaoPerigososEliminados: 1.83; MassaTotalDeResiduosRadioactivosEliminados: 0.000394; EnergiaElectricaExportada: 1.55; MateriaisParaRecuperacaoDeEnergia: 0.00739; MateriaisParaReciclagem: 0.0253; UnidadeEPD: 1 m²
Type - IFC.REVIGRÉS-Dados gerais-Wall Covering - Nome: REVIGRÉS-OMNISTONE-MOLTI-30x30-MATT RECT-ICE; TipoProduto: Prensado a seco: grupo BIa UGL | Grés porcelânico técnico; NumeroDeRegistoDAP: EPD-REV-20240006-CCC1-EN; ReferenciaDAP: -; UrlDOP: -
Classification: C3010 (Uniformat)
Pset_WallCommon - ExtendToStructure: no; LoadBearing: no
IFC.REVIGRÉS-Dados do fabricante-Wall Covering - Type: Basic Wall: REVIGRÉS-OMNISTONE-MOLTI-30X30-MATTRECT-ICE
IFC.REVIGRÉS-Dados de desempenho-Wall Covering - Type: Basic Wall: REVIGRÉS-OMNISTONE-MOLTI-30X30-MATTRECT-ICE
IFC.REVIGRÉS-Dados de especificação-Wall Covering - Type: Basic Wall: REVIGRÉS-OMNISTONE-MOLTI-30X30-MATTRECT-ICE
IFC.REVIGRÉS-Dados geométricos-Wall Covering - Type: Basic Wall: REVIGRÉS-OMNISTONE-MOLTI-30X30-MATTRECT-ICE
IFC.REVIGRÉS-Dados de sustentabilidade-Wall Covering - Type: Basic Wall: REVIGRÉS-OMNISTONE-MOLTI-30X30-MATTRECT-ICE

# IfcWallStandardCase: Basic Wall:REVIGRÉS-OMNISTONE-MOLTI-30X30-MATTRECT-IRON, Basic Wall:REVIGRÉS-OMNISTONE-MOLTI-30X30-MATTRECT-IRON:156302
In: Level 1
Type - PredefinedType: STANDARD; Material: REVIGRÉS-OMNISTONE-MOLTI-30X30-MATTRECT-IRON 9.8 mm
Type - Pset_ElementShading - Roughness: 304.8 mm
Type - Pset_ManufacturerTypeInformation - Manufacturer: REVIGRÉS
Type - Pset_ProductRequirements - Category: Walls
Type - Pset_QuantityTakeOff - Reference: 312B127X81
Type - Pset_ReinforcementBarPitchOfWall - Description: Stone effect in wall and floor porcelain tile; Reference: 312B127X81
Type - Pset_WallCommon - IsExternal: no; Reference: 312B127X81
Type - IFC.REVIGRÉS-Dados do fabricante-Wall Covering - FabricanteURL: https://www.revigres.pt/; ReferenciaModelo: Omnistone; NumeroGlobalDeItemComercial: 312B127X81; Acabamento: MATT RECT; Material: Grés porcelânico; IdentificadorDoOperadorEconomico: 501840856; UrlFabricanteArtigo: https://www.revigres.pt/colecoes/omnistone; PaisOrigem: Portugal
Type - IFC.REVIGRÉS-Dados de desempenho-Wall Covering - Rectilinearidade: ± 0.2% máx.± 0.8 mm; Ortogonalidade: ± 0.2% máx.± 1.5 mm; PlanaridadeDaSuperficie: ± 0.3% máx. ± 1.8 mm; QualidadeDaSuperficie: Cumpre; AbsorcaoDeAgua: < 0.05%; ModuloDeRuptura: > 45 N/mm²; ResistenciaAFlexao: ≥ 3500 N; ResistenciaAAbrasaoProfunda: < 120 mm³; DilatacaoTermicaLinear: ≤ 8,0x10-6 °C-1; ResistenciaAoChoqueTermico: Resiste; DurabilidadeResistenciaAoGeloDegelo: Resiste; ResistenciaAoEscorregamentoDIN51130: R10; ResistenciaAoEscorregamentoDIN51097: B; ResistenciaAoEscorregamentoENV51097: B; ResistenciaAoEscorregamentoENV12633: Class 2; ResistenciaAoEscorregamentoBS7976: >36; ResistenciaAoEscorregamentoANSIA1371: ≥0,42; ResistenciaAoDeslizamentoENV12633: Class 2; ResistenciaAoDeslizamentoBS7976: >36; ResistenciaAsManchas: Class 5; ResistenciaABaixasConcentracoesDeAcidosEAlcalis: Classe LA; ResistenciaAAltasConcentracoesDeAcidosEAlcalis: Classe HA; LibertacaoDeCadmio: 0; LibertacaoDeChumbo: 0
Type - IFC.REVIGRÉS-Dados de especificação-Wall Covering - VariacaoTonalidade: 3; NivelDeTrafego: 5; EPavimento: Sim; ERevestimento: Sim; EExterno: Sim
Type - IFC.REVIGRÉS-Dados geométricos-Wall Covering - AlturaNominal: 9.8 mm; ComprimentoNominal: 29.5 mm; LarguraNominal: 29.5 mm
Type - IFC.REVIGRÉS-Dados de sustentabilidade-Wall Covering - EnergiaTermicaExportada: 0; PotencialPrivacaoDeAguaConsumoDeAguaPonderado: 4.5; ItemENovo: Sim; ItemEParcialmenteReciclado: 0.14; ItemEReciclado: Sim; VidaÚtilEsperada: 50; SubstanciasPerigosas: Não; PotencialDeEsgotamentoAbioticoDosRecursosFosseis: 203; PotencialDeEsgotamentoAbioticoDosRecursosNaoFosseisMineraisEMetais: 0.000701; PotencialDeAquecimentoGlobalBiogenico: -0.48; CombustiveisFosseisComPotencialDeAquecimentoGlobal: 13.9; PotencialDeAquecimentoGlobalUsoDoSoloEMudancaDeUsoDoSolo: 0.0246; PotencialDeEutrofizacaoFraccaoDeNutrientesQueAtingemOCompartimentoFinalDeAguaDoce: 0.000189; PotencialDeEutrofizacaoFraccaoDeNutrientesQueAtingemOCompartimentoFinalMarinho: 0.0122; EnergiaRecuperada: 0.00739; ConsumoDeAguaDoce: 0.113; UtilizacaoLiquidaDeAguaDoce: 0.113; ResiduosPerigososEliminados: 0.00221; ResiduosNaoPerigososEliminados: 1.83; MassaTotalDeResiduosRadioactivosEliminados: 0.000394; EnergiaElectricaExportada: 1.55; MateriaisParaRecuperacaoDeEnergia: 0.00739; MateriaisParaReciclagem: 0.0253; UnidadeEPD: 1 m²
Type - IFC.REVIGRÉS-Dados gerais-Wall Covering - Nome: REVIGRÉS-OMNISTONE-MOLTI-30x30-MATT RECT-IRON; TipoProduto: Prensado a seco: grupo BIa UGL | Grés porcelânico técnico; NumeroDeRegistoDAP: EPD-REV-20240006-CCC1-EN; ReferenciaDAP: -; UrlDOP: -
Classification: C3010 (Uniformat)
Pset_WallCommon - ExtendToStructure: no; LoadBearing: no
IFC.REVIGRÉS-Dados do fabricante-Wall Covering - Type: Basic Wall: REVIGRÉS-OMNISTONE-MOLTI-30X30-MATTRECT-IRON
IFC.REVIGRÉS-Dados de desempenho-Wall Covering - Type: Basic Wall: REVIGRÉS-OMNISTONE-MOLTI-30X30-MATTRECT-IRON
IFC.REVIGRÉS-Dados de especificação-Wall Covering - Type: Basic Wall: REVIGRÉS-OMNISTONE-MOLTI-30X30-MATTRECT-IRON
IFC.REVIGRÉS-Dados geométricos-Wall Covering - Type: Basic Wall: REVIGRÉS-OMNISTONE-MOLTI-30X30-MATTRECT-IRON
IFC.REVIGRÉS-Dados de sustentabilidade-Wall Covering - Type: Basic Wall: REVIGRÉS-OMNISTONE-MOLTI-30X30-MATTRECT-IRON

# IfcWallStandardCase: Basic Wall:REVIGRÉS-OMNISTONE-MOLTI-30X30-MATTRECT-JET, Basic Wall:REVIGRÉS-OMNISTONE-MOLTI-30X30-MATTRECT-JET:156369
In: Level 1
Type - PredefinedType: STANDARD; Material: REVIGRÉS-OMNISTONE-MOLTI-30X30-MATTRECT-JET 9.8 mm
Type - Pset_ElementShading - Roughness: 304.8 mm
Type - Pset_ManufacturerTypeInformation - Manufacturer: REVIGRÉS
Type - Pset_ProductRequirements - Category: Walls
Type - Pset_QuantityTakeOff - Reference: 312B127X91
Type - Pset_ReinforcementBarPitchOfWall - Description: Stone effect in wall and floor porcelain tile; Reference: 312B127X91
Type - Pset_WallCommon - IsExternal: no; Reference: 312B127X91
Type - IFC.REVIGRÉS-Dados do fabricante-Wall Covering - FabricanteURL: https://www.revigres.pt/; ReferenciaModelo: Omnistone; NumeroGlobalDeItemComercial: 312B127X91; Acabamento: MATT RECT; Material: Grés porcelânico; IdentificadorDoOperadorEconomico: 501840856; UrlFabricanteArtigo: https://www.revigres.pt/colecoes/omnistone; PaisOrigem: Portugal
Type - IFC.REVIGRÉS-Dados de desempenho-Wall Covering - Rectilinearidade: ± 0.2% máx.± 0.8 mm; Ortogonalidade: ± 0.2% máx.± 1.5 mm; PlanaridadeDaSuperficie: ± 0.3% máx. ± 1.8 mm; QualidadeDaSuperficie: Cumpre; AbsorcaoDeAgua: < 0.05%; ModuloDeRuptura: > 45 N/mm²; ResistenciaAFlexao: ≥ 3500 N; ResistenciaAAbrasaoProfunda: < 120 mm³; DilatacaoTermicaLinear: ≤ 8,0x10-6 °C-1; ResistenciaAoChoqueTermico: Resiste; DurabilidadeResistenciaAoGeloDegelo: Resiste; ResistenciaAoEscorregamentoDIN51130: R10; ResistenciaAoEscorregamentoDIN51097: B; ResistenciaAoEscorregamentoENV51097: B; ResistenciaAoEscorregamentoENV12633: Class 2; ResistenciaAoEscorregamentoBS7976: >36; ResistenciaAoEscorregamentoANSIA1371: ≥0,42; ResistenciaAoDeslizamentoENV12633: Class 2; ResistenciaAoDeslizamentoBS7976: >36; ResistenciaAsManchas: Class 5; ResistenciaABaixasConcentracoesDeAcidosEAlcalis: Classe LA; ResistenciaAAltasConcentracoesDeAcidosEAlcalis: Classe HA; LibertacaoDeCadmio: 0; LibertacaoDeChumbo: 0
Type - IFC.REVIGRÉS-Dados de especificação-Wall Covering - VariacaoTonalidade: 3; NivelDeTrafego: 5; EPavimento: Sim; ERevestimento: Sim; EExterno: Sim
Type - IFC.REVIGRÉS-Dados geométricos-Wall Covering - AlturaNominal: 9.8 mm; ComprimentoNominal: 29.5 mm; LarguraNominal: 29.5 mm
Type - IFC.REVIGRÉS-Dados de sustentabilidade-Wall Covering - ItemEParcialmenteReciclado: 0; EnergiaTermicaExportada: 0; PotencialPrivacaoDeAguaConsumoDeAguaPonderado: 4.5; ItemENovo: Sim; ItemEReciclado: Não; VidaÚtilEsperada: 50; SubstanciasPerigosas: Não; PotencialDeEsgotamentoAbioticoDosRecursosFosseis: 203; PotencialDeEsgotamentoAbioticoDosRecursosNaoFosseisMineraisEMetais: 0.000701; PotencialDeAquecimentoGlobalBiogenico: -0.48; CombustiveisFosseisComPotencialDeAquecimentoGlobal: 13.9; PotencialDeAquecimentoGlobalUsoDoSoloEMudancaDeUsoDoSolo: 0.0246; PotencialDeEutrofizacaoFraccaoDeNutrientesQueAtingemOCompartimentoFinalDeAguaDoce: 0.000189; PotencialDeEutrofizacaoFraccaoDeNutrientesQueAtingemOCompartimentoFinalMarinho: 0.0122; EnergiaRecuperada: 0.00739; ConsumoDeAguaDoce: 0.113; UtilizacaoLiquidaDeAguaDoce: 0.113; ResiduosPerigososEliminados: 0.00221; ResiduosNaoPerigososEliminados: 1.83; MassaTotalDeResiduosRadioactivosEliminados: 0.000394; EnergiaElectricaExportada: 1.55; MateriaisParaRecuperacaoDeEnergia: 0.00739; MateriaisParaReciclagem: 0.0253; UnidadeEPD: 1 m²
Type - IFC.REVIGRÉS-Dados gerais-Wall Covering - Nome: REVIGRÉS-OMNISTONE-MOLTI-30x30-MATT RECT-JET; TipoProduto: Prensado a seco: grupo BIa UGL | Grés porcelânico técnico; NumeroDeRegistoDAP: EPD-REV-20240006-CCC1-EN; ReferenciaDAP: -; UrlDOP: -
Classification: C3010 (Uniformat)
Pset_WallCommon - ExtendToStructure: no; LoadBearing: no
IFC.REVIGRÉS-Dados do fabricante-Wall Covering - Type: Basic Wall: REVIGRÉS-OMNISTONE-MOLTI-30X30-MATTRECT-JET
IFC.REVIGRÉS-Dados de desempenho-Wall Covering - Type: Basic Wall: REVIGRÉS-OMNISTONE-MOLTI-30X30-MATTRECT-JET
IFC.REVIGRÉS-Dados de especificação-Wall Covering - Type: Basic Wall: REVIGRÉS-OMNISTONE-MOLTI-30X30-MATTRECT-JET
IFC.REVIGRÉS-Dados geométricos-Wall Covering - Type: Basic Wall: REVIGRÉS-OMNISTONE-MOLTI-30X30-MATTRECT-JET
IFC.REVIGRÉS-Dados de sustentabilidade-Wall Covering - Type: Basic Wall: REVIGRÉS-OMNISTONE-MOLTI-30X30-MATTRECT-JET

# IfcWallStandardCase: Basic Wall:REVIGRÉS-OMNISTONE-MOLTI-30X30-MATTRECT-PLATINA, Basic Wall:REVIGRÉS-OMNISTONE-MOLTI-30X30-MATTRECT-PLATINA:156449
In: Level 1
Type - PredefinedType: STANDARD; Material: REVIGRÉS-OMNISTONE-MOLTI-30X30-MATTRECT-PLATINA 9.8 mm
Type - Pset_ElementShading - Roughness: 304.8 mm
Type - Pset_ManufacturerTypeInformation - Manufacturer: REVIGRÉS
Type - Pset_ProductRequirements - Category: Walls
Type - Pset_QuantityTakeOff - Reference: 312B128X01
Type - Pset_ReinforcementBarPitchOfWall - Description: Stone effect in wall and floor porcelain tile; Reference: 312B128X01
Type - Pset_WallCommon - IsExternal: no; Reference: 312B128X01
Type - IFC.REVIGRÉS-Dados do fabricante-Wall Covering - FabricanteURL: https://www.revigres.pt/; ReferenciaModelo: Omnistone; NumeroGlobalDeItemComercial: 312B128X01; Acabamento: MATT RECT; Material: Grés porcelânico; IdentificadorDoOperadorEconomico: 501840856; UrlFabricanteArtigo: https://www.revigres.pt/colecoes/omnistone; PaisOrigem: Portugal
Type - IFC.REVIGRÉS-Dados de desempenho-Wall Covering - Rectilinearidade: ± 0.2% máx.± 0.8 mm; Ortogonalidade: ± 0.2% máx.± 1.5 mm; PlanaridadeDaSuperficie: ± 0.3% máx. ± 1.8 mm; QualidadeDaSuperficie: Cumpre; AbsorcaoDeAgua: < 0.05%; ModuloDeRuptura: > 45 N/mm²; ResistenciaAFlexao: ≥ 3500 N; ResistenciaAAbrasaoProfunda: < 120 mm³; DilatacaoTermicaLinear: ≤ 8,0x10-6 °C-1; ResistenciaAoChoqueTermico: Resiste; DurabilidadeResistenciaAoGeloDegelo: Resiste; ResistenciaAoEscorregamentoDIN51130: R10; ResistenciaAoEscorregamentoDIN51097: B; ResistenciaAoEscorregamentoENV51097: B; ResistenciaAoEscorregamentoENV12633: Class 2; ResistenciaAoEscorregamentoBS7976: >36; ResistenciaAoEscorregamentoANSIA1371: ≥0,42; ResistenciaAoDeslizamentoENV12633: Class 2; ResistenciaAoDeslizamentoBS7976: >36; ResistenciaAsManchas: Class 5; ResistenciaABaixasConcentracoesDeAcidosEAlcalis: Classe LA; ResistenciaAAltasConcentracoesDeAcidosEAlcalis: Classe HA; LibertacaoDeCadmio: 0; LibertacaoDeChumbo: 0
Type - IFC.REVIGRÉS-Dados de especificação-Wall Covering - VariacaoTonalidade: 3; NivelDeTrafego: 5; EPavimento: Sim; ERevestimento: Sim; EExterno: Sim
Type - IFC.REVIGRÉS-Dados geométricos-Wall Covering - AlturaNominal: 9.8 mm; ComprimentoNominal: 29.5 mm; LarguraNominal: 29.5 mm
Type - IFC.REVIGRÉS-Dados de sustentabilidade-Wall Covering - ItemEParcialmenteReciclado: 0; EnergiaTermicaExportada: 0; PotencialPrivacaoDeAguaConsumoDeAguaPonderado: 4.5; ItemENovo: Sim; ItemEReciclado: Não; VidaÚtilEsperada: 50; SubstanciasPerigosas: Não; PotencialDeEsgotamentoAbioticoDosRecursosFosseis: 203; PotencialDeEsgotamentoAbioticoDosRecursosNaoFosseisMineraisEMetais: 0.000701; PotencialDeAquecimentoGlobalBiogenico: -0.48; CombustiveisFosseisComPotencialDeAquecimentoGlobal: 13.9; PotencialDeAquecimentoGlobalUsoDoSoloEMudancaDeUsoDoSolo: 0.0246; PotencialDeEutrofizacaoFraccaoDeNutrientesQueAtingemOCompartimentoFinalDeAguaDoce: 0.000189; PotencialDeEutrofizacaoFraccaoDeNutrientesQueAtingemOCompartimentoFinalMarinho: 0.0122; EnergiaRecuperada: 0.00739; ConsumoDeAguaDoce: 0.113; UtilizacaoLiquidaDeAguaDoce: 0.113; ResiduosPerigososEliminados: 0.00221; ResiduosNaoPerigososEliminados: 1.83; MassaTotalDeResiduosRadioactivosEliminados: 0.000394; EnergiaElectricaExportada: 1.55; MateriaisParaRecuperacaoDeEnergia: 0.00739; MateriaisParaReciclagem: 0.0253; UnidadeEPD: 1 m²
Type - IFC.REVIGRÉS-Dados gerais-Wall Covering - Nome: REVIGRÉS-OMNISTONE-MOLTI-30x30-MATT RECT-PLATINA; TipoProduto: Prensado a seco: grupo BIa UGL | Grés porcelânico técnico; NumeroDeRegistoDAP: EPD-REV-20240006-CCC1-EN; ReferenciaDAP: -; UrlDOP: -
Classification: C3010 (Uniformat)
Pset_WallCommon - ExtendToStructure: no; LoadBearing: no
IFC.REVIGRÉS-Dados do fabricante-Wall Covering - Type: Basic Wall: REVIGRÉS-OMNISTONE-MOLTI-30X30-MATTRECT-PLATINA
IFC.REVIGRÉS-Dados de desempenho-Wall Covering - Type: Basic Wall: REVIGRÉS-OMNISTONE-MOLTI-30X30-MATTRECT-PLATINA
IFC.REVIGRÉS-Dados de especificação-Wall Covering - Type: Basic Wall: REVIGRÉS-OMNISTONE-MOLTI-30X30-MATTRECT-PLATINA
IFC.REVIGRÉS-Dados geométricos-Wall Covering - Type: Basic Wall: REVIGRÉS-OMNISTONE-MOLTI-30X30-MATTRECT-PLATINA
IFC.REVIGRÉS-Dados de sustentabilidade-Wall Covering - Type: Basic Wall: REVIGRÉS-OMNISTONE-MOLTI-30X30-MATTRECT-PLATINA

# IfcWallStandardCase: Basic Wall:REVIGRÉS-OMNISTONE-MOLTI-30X30-MATTRECT-ROPE, Basic Wall:REVIGRÉS-OMNISTONE-MOLTI-30X30-MATTRECT-ROPE:156532
In: Level 1
Type - PredefinedType: STANDARD; Material: REVIGRÉS-OMNISTONE-MOLTI-30X30-MATTRECT-ROPE 9.8 mm
Type - Pset_ElementShading - Roughness: 304.8 mm
Type - Pset_ManufacturerTypeInformation - Manufacturer: REVIGRÉS
Type - Pset_ProductRequirements - Category: Walls
Type - Pset_QuantityTakeOff - Reference: 312B128X11
Type - Pset_ReinforcementBarPitchOfWall - Description: Stone effect in wall and floor porcelain tile; Reference: 312B128X11
Type - Pset_WallCommon - IsExternal: no; Reference: 312B128X11
Type - IFC.REVIGRÉS-Dados do fabricante-Wall Covering - FabricanteURL: https://www.revigres.pt/; ReferenciaModelo: Omnistone; NumeroGlobalDeItemComercial: 312B128X11; Acabamento: MATT RECT; Material: Grés porcelânico; IdentificadorDoOperadorEconomico: 501840856; UrlFabricanteArtigo: https://www.revigres.pt/colecoes/omnistone; PaisOrigem: Portugal
Type - IFC.REVIGRÉS-Dados de desempenho-Wall Covering - Rectilinearidade: ± 0.2% máx.± 0.8 mm; Ortogonalidade: ± 0.2% máx.± 1.5 mm; PlanaridadeDaSuperficie: ± 0.3% máx. ± 1.8 mm; QualidadeDaSuperficie: Cumpre; AbsorcaoDeAgua: < 0.05%; ModuloDeRuptura: > 45 N/mm²; ResistenciaAFlexao: ≥ 3500 N; ResistenciaAAbrasaoProfunda: < 120 mm³; DilatacaoTermicaLinear: ≤ 8,0x10-6 °C-1; ResistenciaAoChoqueTermico: Resiste; DurabilidadeResistenciaAoGeloDegelo: Resiste; ResistenciaAoEscorregamentoDIN51130: R10; ResistenciaAoEscorregamentoDIN51097: B; ResistenciaAoEscorregamentoENV51097: B; ResistenciaAoEscorregamentoENV12633: Class 2; ResistenciaAoEscorregamentoBS7976: >36; ResistenciaAoEscorregamentoANSIA1371: ≥0,42; ResistenciaAoDeslizamentoENV12633: Class 2; ResistenciaAoDeslizamentoBS7976: >36; ResistenciaAsManchas: Class 5; ResistenciaABaixasConcentracoesDeAcidosEAlcalis: Classe LA; ResistenciaAAltasConcentracoesDeAcidosEAlcalis: Classe HA; LibertacaoDeCadmio: 0; LibertacaoDeChumbo: 0
Type - IFC.REVIGRÉS-Dados de especificação-Wall Covering - VariacaoTonalidade: 3; NivelDeTrafego: 5; EPavimento: Sim; ERevestimento: Sim; EExterno: Sim
Type - IFC.REVIGRÉS-Dados geométricos-Wall Covering - AlturaNominal: 9.8 mm; ComprimentoNominal: 29.5 mm; LarguraNominal: 29.5 mm
Type - IFC.REVIGRÉS-Dados de sustentabilidade-Wall Covering - ItemEParcialmenteReciclado: 0; EnergiaTermicaExportada: 0; PotencialPrivacaoDeAguaConsumoDeAguaPonderado: 4.5; ItemENovo: Sim; ItemEReciclado: Não; VidaÚtilEsperada: 50; SubstanciasPerigosas: Não; PotencialDeEsgotamentoAbioticoDosRecursosFosseis: 203; PotencialDeEsgotamentoAbioticoDosRecursosNaoFosseisMineraisEMetais: 0.000701; PotencialDeAquecimentoGlobalBiogenico: -0.48; CombustiveisFosseisComPotencialDeAquecimentoGlobal: 13.9; PotencialDeAquecimentoGlobalUsoDoSoloEMudancaDeUsoDoSolo: 0.0246; PotencialDeEutrofizacaoFraccaoDeNutrientesQueAtingemOCompartimentoFinalDeAguaDoce: 0.000189; PotencialDeEutrofizacaoFraccaoDeNutrientesQueAtingemOCompartimentoFinalMarinho: 0.0122; EnergiaRecuperada: 0.00739; ConsumoDeAguaDoce: 0.113; UtilizacaoLiquidaDeAguaDoce: 0.113; ResiduosPerigososEliminados: 0.00221; ResiduosNaoPerigososEliminados: 1.83; MassaTotalDeResiduosRadioactivosEliminados: 0.000394; EnergiaElectricaExportada: 1.55; MateriaisParaRecuperacaoDeEnergia: 0.00739; MateriaisParaReciclagem: 0.0253; UnidadeEPD: 1 m²
Type - IFC.REVIGRÉS-Dados gerais-Wall Covering - Nome: REVIGRÉS-OMNISTONE-MOLTI-30x30-MATT RECT-ROPE; TipoProduto: Prensado a seco: grupo BIa UGL | Grés porcelânico técnico; NumeroDeRegistoDAP: EPD-REV-20240006-CCC1-EN; ReferenciaDAP: -; UrlDOP: -
Classification: C3010 (Uniformat)
Pset_WallCommon - ExtendToStructure: no; LoadBearing: no
IFC.REVIGRÉS-Dados do fabricante-Wall Covering - Type: Basic Wall: REVIGRÉS-OMNISTONE-MOLTI-30X30-MATTRECT-ROPE
IFC.REVIGRÉS-Dados de desempenho-Wall Covering - Type: Basic Wall: REVIGRÉS-OMNISTONE-MOLTI-30X30-MATTRECT-ROPE
IFC.REVIGRÉS-Dados de especificação-Wall Covering - Type: Basic Wall: REVIGRÉS-OMNISTONE-MOLTI-30X30-MATTRECT-ROPE
IFC.REVIGRÉS-Dados geométricos-Wall Covering - Type: Basic Wall: REVIGRÉS-OMNISTONE-MOLTI-30X30-MATTRECT-ROPE
IFC.REVIGRÉS-Dados de sustentabilidade-Wall Covering - Type: Basic Wall: REVIGRÉS-OMNISTONE-MOLTI-30X30-MATTRECT-ROPE
